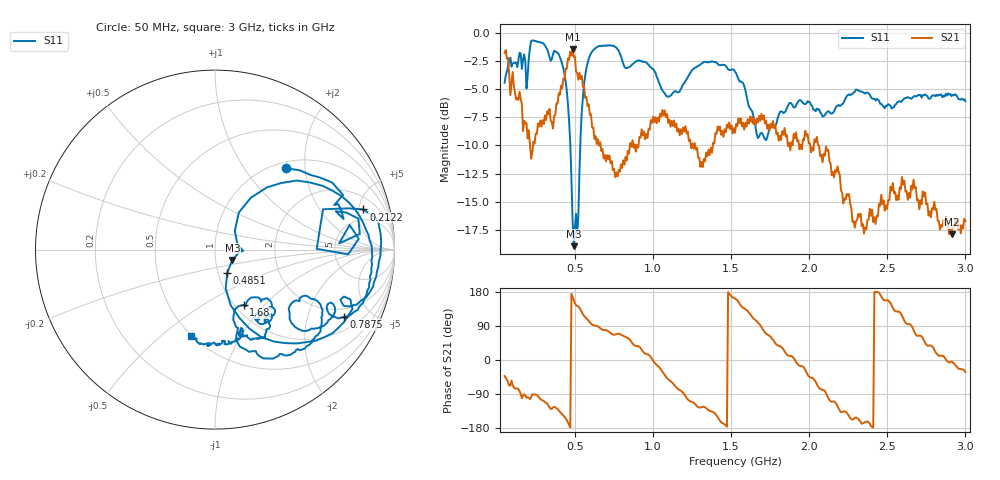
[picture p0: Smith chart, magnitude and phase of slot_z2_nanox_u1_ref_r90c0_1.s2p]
! nanovna_capture.py 2026-10-26T21:31:37+0900
! NanoVNA-F_V2 fw 0.6.0 SN 4A3639384505514B
! cal: load open short thru cal'ed  over 50000000-3000000000 Hz, 201 points
! points 401, avg 4
! slot line z=1.6, genuine Nano X, 90 deg (length along slot, USB toward PORT 1), centred
# HZ S RI R 50
! S12 and S22 are not measured (written as 0)
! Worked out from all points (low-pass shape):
!   401 points, 50 MHz to 3 GHz, reference 50 ohm
!   highest |S21| = -1.45 dB at 485.1 MHz (marker M1); lowest = -17.9 dB at 2.912 GHz (marker M2)
!   |S21| within 3 dB of the highest: start of sweep to 82.4 MHz; 422.7 MHz to 549 MHz (126.3 MHz wide, 26 % of centre) (the widest 2 of 3)
!   lowest |S11| = -19.0 dB at 492.5 MHz (marker M3), VSWR 1.25, Z = 60.3 - j7 ohm
!   |S11| at or under -10 dB: 470.8 MHz to 534.6 MHz (63.8 MHz wide, 12.7 % of centre)
!   S12 and S22 are empty: the file has one direction only
!   S11 on the Smith chart (normalised r, x): 50 MHz: 1.12, +1.59; 212.2 MHz: 3.33, +5.58; 485.1 MHz: 1.10, -0.29; 787.5 MHz: 1.56, -3.40; 1.68 GHz: 1.10, -0.77; 3 GHz: 0.50, -0.64
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5e7  0.3948 0.4534  0.605 -0.5491  0 0  0 0
1.75375e8  0.8007 0.0597  -0.00326 -0.4073  0 0  0 0
2.1225e8  0.8266 0.2239  -0.0729 -0.3102  0 0  0 0
2.86e8  0.8873 -0.1772  -0.0999 -0.37  0 0  0 0
4.1875e8  0.5101 -0.5153  -0.4564 -0.3377  0 0  0 0
4.85125e8  0.0677 -0.1307  -0.8233 0.1946  0 0  0 0
4.925e8  0.097 -0.0573  -0.7276 0.2878  0 0  0 0
5.0725e8  0.1568 -0.00654  -0.5496 0.39  0 0  0 0
5.44125e8  0.2879 0.346  -0.3792 0.521  0 0  0 0
6.32625e8  0.8552 0.0818  -0.00331 0.3477  0 0  0 0
7.875e8  0.7178 -0.3755  0.0903 0.224  0 0  0 0
1.03825e9  0.4331 -0.417  0.3827 -0.1283  0 0  0 0
1.207875e9  0.5476 -0.2758  -0.0349 -0.3836  0 0  0 0
1.525e9  0.2908 -0.6069  -0.3433 0.1096  0 0  0 0
1.679875e9  0.1599 -0.3081  -0.0393 0.4265  0 0  0 0
1.842125e9  0.3071 -0.3199  0.3471 0.1498  0 0  0 0
2.019125e9  0.2417 -0.4078  0.2098 -0.2287  0 0  0 0
2.196125e9  0.2753 -0.3849  -0.1605 -0.1691  0 0  0 0
2.351e9  0.2152 -0.4966  -0.1243 -0.0313  0 0  0 0
2.51325e9  0.1385 -0.4593  -0.1616 0.0806  0 0  0 0
2.9115e9  -0.0437 -0.5222  0.1267 -0.00888  0 0  0 0
3e9  -0.1309 -0.4799  0.1239 -0.0762  0 0  0 0
